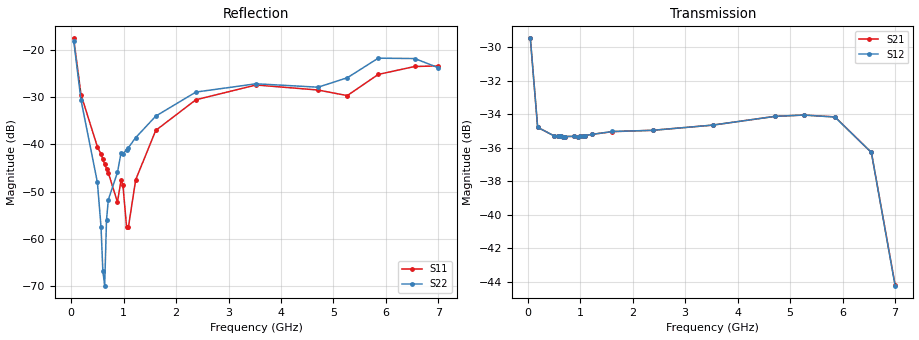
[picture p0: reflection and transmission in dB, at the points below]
! Integrated Device Technology
! Corporate Headquarters
! 6024 Silver Creek Valley Road
! San Jose, CA 95138  USA
! Phone:  1-408-284-8200
! Toll Free:  1-800-223-1366
! Webpage:  http://www.idt.com/
! Timing and RF Division
! 515 Groton Road, Suite 102
! Westford, MA 01886-6024
! Device:  F2258
! Description: Voltage Variable RF Attenuator
! Frequency:  50.0 -  6000.00 MHz
! Package:  3x3 mm Thin QFN Plastic Package: 16 pin
! Ports:  2 RF, 2 DC
!  Pin  1  = NC
!  Pin  2  = NC
!  Pin  3  = RF2  = Port 2
!  Pin  4  = GND
!  Pin  5  = Vdd
!  Pin  6  = NC
!  Pin  7  = VCTRL
!  Pin  8  = NC
!  Pin  9  = GND
!  Pin 10  = RF1  = Port 1
!  Pin 11  = NC
!  Pin 12  = NC
!  Pin 13  = NC
!  Pin 14  = NC
!  Pin 15  = NC
!  Pin 16  = NC
! Vcntrl:  2.160 Volts
! Vdd:  +3.300 Volts
! Current:  1.152 mA
! Data:  The device was measured on a the F2258 evaluation board which has
!  individual transmission lines to the RF pins.  Data was collected
!  using a calibrated network analyzer.  The evaluation board was
!  de-embedded using a TRL calibration technique.
!  The reference plane is the edge of the package pin.
! Misc:  SN 10
!  Action Tracker AT0285
! Date Measured:  2014-12-10
! Date:  2016-01-13  MJV
! Note:
!  Integrated Device Technology supplies this data as a sample of measured
!  data at the package pin for this product.  Your particular data for this
!  product may vary.
!  Data was taken at 25 degrees C.
!  Integrated Device Technology reserves the right to change this data at anytime.
!Freq_(GHz)  S11M_(dB)  S11P_(deg)  S21M_(dB)  S21P_(deg)  S12M_(dB)  S12P_(deg)  S22M_(dB)  S22P_(deg)
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# GHz S dB R 50
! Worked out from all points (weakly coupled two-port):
!   201 points, 50 MHz to 7 GHz, reference 50 ohm
!   highest |S21| = -29.48 dB at 50 MHz (marker M1); lowest = -44.2 dB at 7 GHz (marker M2)
!   lowest |S11| = -57.5 dB at 1.093 GHz (marker M3), VSWR 1.00, Z = 49.9 + j0.116 ohm
!   |S11| at or under -10 dB: start of sweep to end of sweep
!   |S22| runs from -69.9 to -18.0 dB; largest |S21 - S12| = 8.3e-05
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0.05  -17.55 -111.0  -29.48 -68.0  -29.48 -68.0  -18.01 -110.6
0.189  -29.43 -109.4  -34.78 -24.5  -34.78 -24.5  -30.55 -104.0
0.50175  -40.48 -121.8  -35.29 -11.2  -35.29 -11.2  -48.01 -102.6
0.57125  -42.08 -124.7  -35.31 -10.4  -35.31 -10.3  -57.45 -99.6
0.606  -43.06 -126.4  -35.31 -10.0  -35.32 -10.0  -66.81 -116.1
0.64075  -44.19 -128.0  -35.32 -9.7  -35.32 -9.7  -69.87 65.4
0.6755  -45.14 -132.0  -35.33 -9.4  -35.33 -9.4  -56.00 71.1
0.71025  -46.00 -137.8  -35.33 -9.2  -35.33 -9.2  -51.65 85.2
0.884  -52.18 166.1  -35.32 -8.5  -35.32 -8.5  -45.91 87.0
0.9535  -47.54 -162.6  -35.33 -8.3  -35.33 -8.3  -41.73 104.8
0.98825  -48.62 -174.6  -35.31 -8.2  -35.31 -8.2  -42.00 101.9
1.05775  -57.40 155.5  -35.29 -8.1  -35.29 -8.0  -41.08 85.6
1.0925  -57.51 119.0  -35.27 -8.0  -35.27 -8.0  -40.66 82.3
1.2315  -47.46 47.7  -35.20 -8.0  -35.20 -8.0  -38.55 63.1
1.61375  -37.02 32.8  -35.04 -9.7  -35.03 -9.8  -34.00 43.9
2.37825  -30.54 48.2  -34.96 -13.4  -34.96 -13.4  -28.91 38.2
3.525  -27.41 91.7  -34.65 -19.9  -34.65 -19.9  -27.16 63.8
4.7065  -28.48 95.6  -34.13 -29.1  -34.13 -29.0  -27.88 55.3
5.2625  -29.66 54.4  -34.05 -35.2  -34.05 -35.2  -25.89 17.8
5.85325  -25.18 29.9  -34.16 -45.7  -34.17 -45.8  -21.74 -4.6
6.54825  -23.50 45.0  -36.28 -66.4  -36.28 -66.4  -21.82 -39.4
7  -23.38 84.4  -44.17 -62.1  -44.22 -61.4  -23.77 -129.4
